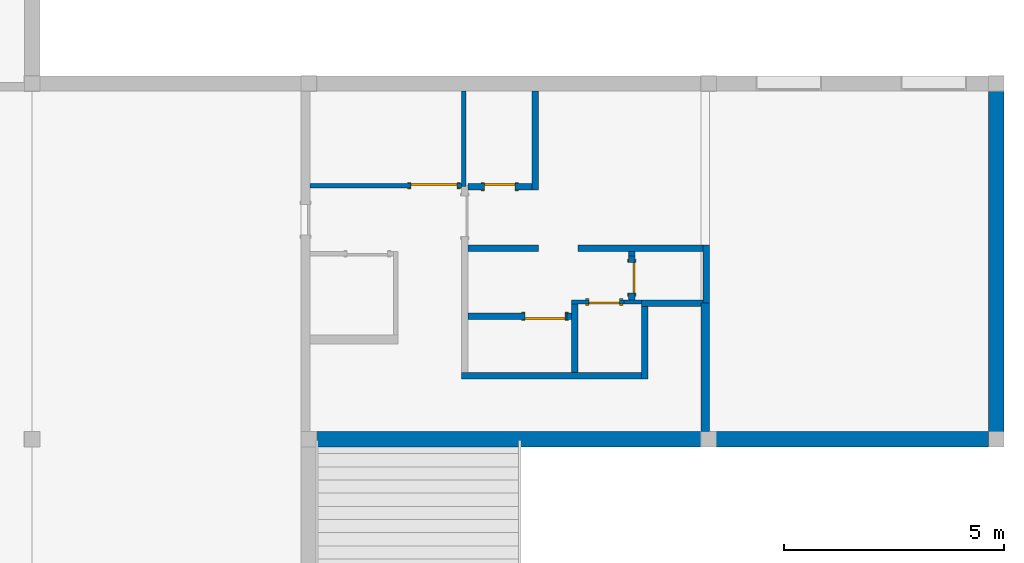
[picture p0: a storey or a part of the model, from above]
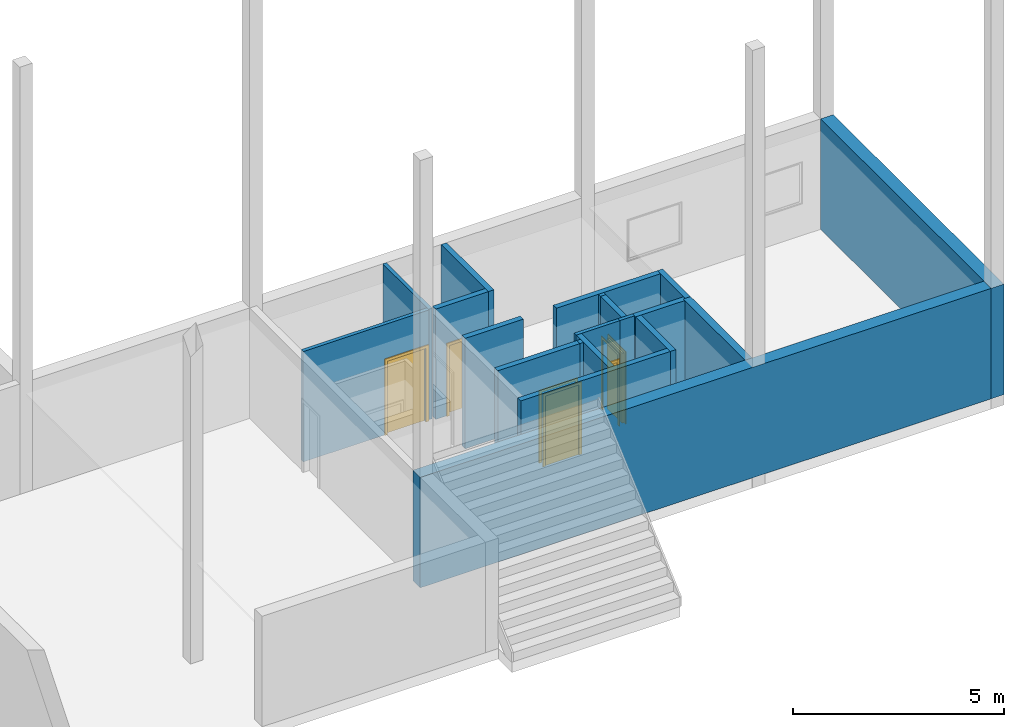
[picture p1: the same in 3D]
Properties of the parts of a building model (IFC2X3)

# File
Description: ViewDefinition [CoordinationView_V2.0]
File name: Project Number
Time: 2023-11-21T13:42:55+03:30
Written by: ODA SDAI 22.12
Made in: 23.0.10.18 - Exporter 23.0.10.18 - Alternate UI 23.0.10.18

# IfcProject, Project Number
LongName: Project Name; Phase: Project Status

# IfcSite, Default
RefLatitude: 42, 12, 46, 799999; RefLongitude: -71, -1, -58, -799999; RefElevation: 0 m
Pset_ProductRequirements - Category: Project Information

# IfcSite: Toyota_Prius_2007_8010:Toyota_Prius_2007_8010 (2)
Material: <Unnamed>
Pset_ProductRequirements - Category: Site
Name (Toyota_Prius_2007_8010:Toyota_Prius_2007_8010:...)
230649
230872

# IfcSite: Volvo-850_4217:Volvo-850_4217 (2)
Material: <Unnamed>
Pset_ProductRequirements - Category: Site
Name (Volvo-850_4217:Volvo-850_4217:...)
229891
230032

# IfcBuilding
Pset_BuildingCommon - NumberOfStoreys: 3
Pset_ProductRequirements - Category: Project Information

# IfcBuildingStorey: Level:8mm Head (3)
Pset_ProductRequirements - Category: Levels
Name | LongName = Pset_AirSideSystemInformation, Name = Pset_ProductRequirements, Name | Elevation (m)
B1 | B1 | -2.3
G0 | G0 | 1.2
F1 | F1 | 5.64

# IfcColumn: COLUMN:COLUMN, COLUMN:COLUMN:227022
In: B1
Type - PredefinedType: COLUMN
Type - Pset_ColumnCommon - IsExternal: no
Type - Pset_ProductRequirements - Category: Columns
Pset_ColumnCommon - Reference: COLUMN
Pset_QuantityTakeOff - Reference: COLUMN; sets with these values: 2

# IfcCovering: Compound Ceiling:Plain (9)
Type - PredefinedType: CEILING
Type - Pset_CoveringCommon - TotalThickness: 0.057 m
Type - Pset_ElementShading - Roughness: 0.3048 m
Type - Pset_ProductRequirements - Category: Ceilings
Material: Metal - Stud Layer 0.045 m, Plasterboard 0.012 m
Pset_CoveringCommon - Reference: Plain; sets with these values: 2
Name (Compound Ceiling:Plain:...) | In
231957 | B1
232175 | B1
232232 | B1
232270 | G0
232307 | G0
232344 | G0
232768 | F1
232807 | F1
232842 | F1

# IfcCovering: Roof Soffit:Generic - 300mm, Roof Soffit:Generic - 300mm:256773
In: F1
Type - PredefinedType: CEILING
Type - Pset_CoveringCommon - TotalThickness: 0.3 m
Type - Pset_ProductRequirements - Category: Roofs: Roof Soffits
Material: Default Roof 0.3 m
Pset_CoveringCommon - Reference: Generic - 300mm; sets with these values: 2

# IfcDoor: Double_8_lite_patio_door_5282:36x2" x 80" w/transom" (4)
Type - ParameterTakesPrecedence: no; Sizeable: no; Classification: C1020 (Uniformat); Material: <Unnamed>, Door - Panel (8), Glazing - Window Glazing (3), Finishes - Exterior - Trim (4), Finishes - Interior - Trim
Type - Pset_DoorCommon - IsExternal: no
Type - Pset_ProductRequirements - Category: Doors
OverallHeight: 2.4384 m; OverallWidth: 1.8288 m
Pset_DoorCommon - Reference: 36x2" x 80" w/transom"
Pset_QuantityTakeOff - Reference: 36x2" x 80" w/transom"
Name (Double_8_lite_patio_door_5282:36x2" x 80" w/transom":...) | In
226973 | B1
227042 | G0 | Material: <Unnamed>, Door - Panel, Glazing - Window Glazing, Finishes - Exterior - Trim, Finishes - Interior - Trim
227043 | G0
227113 | F1 | Material: <Unnamed>, Door - Panel, Glazing - Window Glazing, Finishes - Exterior - Trim, Finishes - Interior - Trim

# IfcDoor: M_Single-Flush:0762 x 2032mm (17)
Type - ParameterTakesPrecedence: no; Sizeable: no; Material: Door - Frame (2), Door - Panel
Type - Pset_DoorCommon - IsExternal: no
Type - Pset_ProductRequirements - Category: Doors
OverallHeight: 2.032 m; OverallWidth: 0.7 m
Pset_DoorCommon - Reference: 0762 x 2032mm
Pset_QuantityTakeOff - Reference: 0762 x 2032mm
Name (M_Single-Flush:0762 x 2032mm:...) | In | Material
227198 | F1
227199 | F1
227200 | F1 | Door - Frame, Door - Panel
227201 | F1 | Door - Frame, Door - Panel
227202 | F1 | Door - Frame, Door - Panel
227203 | F1 | Door - Frame, Door - Panel
227204 | F1 | Door - Frame, Door - Panel
227205 | F1 | Door - Frame, Door - Panel
227206 | F1 | Door - Frame, Door - Panel
227211 | G0 | Door - Frame, Door - Panel
227212 | G0 | Door - Frame, Door - Panel
227213 | G0 | Door - Frame, Door - Panel
227214 | G0 | Door - Frame, Door - Panel
227215 | B1
227216 | B1 | Door - Frame, Door - Panel
227217 | B1 | Door - Frame, Door - Panel
227218 | B1 | Door - Frame, Door - Panel

# IfcDoor: M_Single-Flush:0915 x 2032mm (3)
In: B1
Type - ParameterTakesPrecedence: no; Sizeable: no; Material: Door - Frame (2), Door - Panel
Type - Pset_DoorCommon - IsExternal: no
Type - Pset_ProductRequirements - Category: Doors
OverallHeight: 2.032 m; OverallWidth: 0.915 m
Pset_DoorCommon - Reference: 0915 x 2032mm
Pset_QuantityTakeOff - Reference: 0915 x 2032mm
Name (M_Single-Flush:0915 x 2032mm:...)
226975
226976
226977

# IfcDoor: M_Single-Flush:0915 x 2134mm (6)
Type - ParameterTakesPrecedence: no; Sizeable: no; Material: Door - Frame (2), Door - Panel
Type - Pset_DoorCommon - IsExternal: no
Type - Pset_ProductRequirements - Category: Doors
OverallHeight: 2.134 m; OverallWidth: 1.05 m
Pset_DoorCommon - Reference: 0915 x 2134mm
Pset_QuantityTakeOff - Reference: 0915 x 2134mm
Name (M_Single-Flush:0915 x 2134mm:...) | In | Material
226974 | B1
226996 | G0
226997 | G0 | Door - Frame, Door - Panel
226999 | G0 | Door - Frame, Door - Panel
227009 | G0 | Door - Frame, Door - Panel
227010 | G0 | Door - Frame, Door - Panel

# IfcDoor: Parametric_Operable_Sliding_Door_6386.0004:3000W x 2400H (2)
In: F1
Type - ParameterTakesPrecedence: no; Sizeable: no; Material: Window Glass (2), Window Frame (2)
Type - Pset_DoorCommon - IsExternal: no
Type - Pset_ProductRequirements - Category: Doors
Type - IfcPermeableCoveringProperties - FrameThickness: 0.05 m
OverallHeight: 2.2 m; OverallWidth: 1 m
Pset_DoorCommon - Reference: 3000W x 2400H
Pset_QuantityTakeOff - Reference: 3000W x 2400H
Name (Parametric_Operable_Sliding_Door_6386.0004:3000W x 2400H:...)
227209
227210 | Material: Window Glass, Window Frame

# IfcDoor: Parametric_Operable_Sliding_Door_6386.0004:5M (3)
Type - ParameterTakesPrecedence: no; Sizeable: no; Material: Window Glass (2), Window Frame (2)
Type - Pset_DoorCommon - IsExternal: no
Type - Pset_ProductRequirements - Category: Doors
Type - IfcPermeableCoveringProperties - FrameThickness: 0.05 m
OverallHeight: 2.2 m; OverallWidth: 5 m
Pset_DoorCommon - Reference: 5M
Pset_QuantityTakeOff - Reference: 5M
Name (Parametric_Operable_Sliding_Door_6386.0004:5M:...) | In | Material
227177 | F1
227988 | F1 | Window Glass, Window Frame
228184 | G0 | Window Glass, Window Frame

# IfcMember: Stringer:Stringer - 50 mm Width (2)
In: B1
Type - PredefinedType: STRINGER
Material: <Unnamed>
Pset_MemberCommon - IsExternal: no; Reference: Stringer - 50 mm Width; Slope: 90 deg
Pset_ProductRequirements - Category: Stairs: Supports
Pset_QuantityTakeOff - Reference: Stringer - 50 mm Width
Name (Assembled Stair:Stair:...)
228969 Stringer 1
228969 Stringer 2

# IfcOpeningElement: Opening (44)
Name | In
Basic Wall:CW 100:227006 | G0 | Pset_OpeningElementCommon - Reference: 0915 x 2134mm; sets with these values: 2; Pset_ProductRequirements - Category: Doors
M_Fixed:0915 x 1220mm:227227:1 | B1
M_Fixed:0915 x 1220mm:227228:1 | B1
Double_8_lite_patio_door_5282:36x2" x 80" w/transom":226973:1 | B1
M_Single-Flush:0762 x 2032mm:227218:1 | B1
M_Single-Flush:0915 x 2032mm:226976:1 | B1
M_Single-Flush:0915 x 2134mm:226974:1 | B1
M_Single-Flush:0762 x 2032mm:227217:1 | B1
M_Single-Flush:0915 x 2032mm:226975:1 | B1
M_Single-Flush:0915 x 2032mm:226977:1 | B1
M_Single-Flush:0762 x 2032mm:227216:1 | B1
M_Single-Flush:0762 x 2032mm:227215:1 | B1
M_Fixed:0915 x 1830mm:227056:1 | G0
M_Fixed:0915 x 1220mm:227219:1 | G0
M_Fixed:0915 x 1220mm:227220:1 | G0
Double_8_lite_patio_door_5282:36x2" x 80" w/transom":227043:1 | G0
Parametric_Operable_Sliding_Door_6386.0004:5M:228184:1 | G0
M_Single-Flush:0762 x 2032mm:227214:1 | G0
Double_8_lite_patio_door_5282:36x2" x 80" w/transom":227042:1 | G0
M_Single-Flush:0762 x 2032mm:227211:1 | G0
M_Single-Flush:0915 x 2134mm:226996:1 | G0
M_Single-Flush:0762 x 2032mm:227212:1 | G0
M_Single-Flush:0762 x 2032mm:227213:1 | G0
M_Single-Flush:0915 x 2134mm:226997:1 | G0
M_Single-Flush:0915 x 2134mm:226999:1 | G0
M_Single-Flush:0915 x 2134mm:227010:1 | G0
M_Single-Flush:0915 x 2134mm:227009:1 | G0
M_Single-Flush:0762 x 2032mm:227198:1 | F1
Parametric_Operable_Sliding_Door_6386.0004:5M:227988:1 | F1
M_Fixed:0915 x 1220mm:227196:1 | F1
M_Fixed:0915 x 1220mm:227197:1 | F1
Parametric_Operable_Sliding_Door_6386.0004:3000W x 2400H:227210:1 | F1
Parametric_Operable_Sliding_Door_6386.0004:3000W x 2400H:227209:1 | F1
M_Single-Flush:0762 x 2032mm:227204:1 | F1
M_Single-Flush:0762 x 2032mm:227205:1 | F1
Double_8_lite_patio_door_5282:36x2" x 80" w/transom":227113:1 | F1
M_Fixed:0915 x 1220mm:227114:1 | F1
Parametric_Operable_Sliding_Door_6386.0004:5M:227177:1 | F1
M_Single-Flush:0762 x 2032mm:227206:1 | F1
M_Single-Flush:0762 x 2032mm:227201:1 | F1
M_Single-Flush:0762 x 2032mm:227199:1 | F1
M_Single-Flush:0762 x 2032mm:227200:1 | F1
M_Single-Flush:0762 x 2032mm:227203:1 | F1
M_Single-Flush:0762 x 2032mm:227202:1 | F1

# IfcRailing: Railing:1100mm (5)
Pset_ProductRequirements - Category: Railings
Pset_QuantityTakeOff - Reference: 1100mm
Pset_RailingCommon - IsExternal: no; Reference: 1100mm; Height: 1.2192 m
Name (Railing:1100mm:...) | In | Material
227187 | F1 | <Unnamed> (26)
227192 | F1 | <Unnamed> (48)
227223 | G0 | <Unnamed> (48)
228103 | F1 | <Unnamed> (25)
228249 | G0 | <Unnamed> (25)

# IfcSlab: Floor:Generic 300mm (4)
Type - PredefinedType: FLOOR; Material: Default Floor 0.3 m
Type - Pset_ElementShading - Roughness: 0.3048 m
Type - Pset_ProductRequirements - Category: Floors
Type - Pset_SlabCommon - IsExternal: no
Pset_QuantityTakeOff - Reference: Generic 300mm; sets with these values: 2
Pset_SlabCommon - LoadBearing: no; Reference: Generic 300mm; PitchAngle: 0 deg
Name (Floor:Generic 300mm:...) | In
227025 | B1
227046 | G0
227059 | F1
227180 | F1

# IfcStair: Assembled Stair:190mm max riser 250mm going, Assembled Stair:Stair:228969
In: B1
ShapeType: STRAIGHT_RUN_STAIR
Pset_ProductRequirements - Category: Stairs
Pset_QuantityTakeOff - Reference: 190mm max riser 250mm going
Pset_StairCommon - IsExternal: no; Reference: 190mm max riser 250mm going; NumberOfRiser: 14; NumberOfTreads: 13; RiserHeight: 0.264 m; TreadLength: 0.3 m

# IfcStairFlight: Non-Monolithic Run:50 mm Tread 13 mm Riser, Assembled Stair:Stair:228969 Run 1
In: B1
Type - PredefinedType: STRAIGHT
Type - Pset_ProductRequirements - Category: Stairs: Runs
Type - Pset_StairFlightCommon - NosingLength: 0 m
NumberOfRiser: 14; NumberOfTreads: 13; RiserHeight: 0.866142 m; TreadLength: 0.984252 m; Material: <Unnamed>
Pset_QuantityTakeOff - Reference: 50 mm Tread 13 mm Riser
Pset_StairFlightCommon - Reference: 50 mm Tread 13 mm Riser; NumberOfRiser: 14; NumberOfTreads: 13; RiserHeight: 0.264 m; TreadLength: 0.3 m; WalkingLineOffset: 7.48336 m; TreadLengthAtOffset: 0.3 m; TreadLengthAtInnerSide: 0.3 m

# IfcWallStandardCase: Basic Wall:CW 100 (53)
Type - PredefinedType: STANDARD; Material: Masonry - Concrete Block 0.1 m
Type - Pset_ElementShading - Roughness: 0.3048 m
Type - Pset_ProductRequirements - Category: Walls
Type - Pset_WallCommon - IsExternal: yes
Pset_QuantityTakeOff - Reference: CW 100; sets with these values: 2
Pset_WallCommon - ExtendToStructure: no; LoadBearing: no; Reference: CW 100
Name (Basic Wall:CW 100:...) | In
226934 | B1
226935 | B1
226936 | B1
226937 | B1
226952 | B1
226953 | B1
226979 | G0
226980 | G0
226981 | G0
226982 | G0
226983 | G0
226984 | G0
226985 | G0
226986 | G0
226989 | G0
226990 | G0
226991 | G0
226992 | G0
226993 | G0
226994 | G0
226995 | G0
226998 | G0
227000 | G0
227003 | G0
227004 | G0
227005 | G0
227006 | G0
227007 | G0
227008 | G0
227055 | G0
227078 | F1
227079 | F1
227080 | F1
227081 | F1
227082 | F1
227091 | F1
227092 | F1
227093 | F1
227094 | F1
227095 | F1
227096 | F1
227097 | F1
227098 | F1
227099 | F1
227100 | F1
227101 | F1
227102 | F1
227103 | F1
227104 | F1
227105 | F1
227106 | F1
227111 | F1
227112 | F1

# IfcWallStandardCase: Basic Wall:CW 102-50-100p (4)
In: B1
Type - PredefinedType: STANDARD; Material: Masonry - Concrete Block 0.35 m
Type - Pset_ElementShading - Roughness: 0.3048 m
Type - Pset_ProductRequirements - Category: Walls
Type - Pset_WallCommon - IsExternal: yes
Pset_QuantityTakeOff - Reference: CW 102-50-100p; sets with these values: 2
Pset_WallCommon - ExtendToStructure: no; LoadBearing: no; Reference: CW 102-50-100p
Name (Basic Wall:CW 102-50-100p:...)
226925
226926
226927
227776

# IfcWallStandardCase: Basic Wall:CW 150 (22)
Type - PredefinedType: STANDARD; Material: Masonry - Concrete Block 0.15 m
Type - Pset_ElementShading - Roughness: 0.3048 m
Type - Pset_ProductRequirements - Category: Walls
Type - Pset_WallCommon - IsExternal: yes
Pset_QuantityTakeOff - Reference: CW 150; sets with these values: 2
Pset_WallCommon - ExtendToStructure: no; LoadBearing: no; Reference: CW 150
Name (Basic Wall:CW 150:...) | In
226938 | B1
226939 | B1
226941 | B1
226942 | B1
226943 | B1
226944 | B1
226945 | B1
226946 | B1
226947 | B1
226948 | B1
226949 | B1
226950 | B1
226951 | B1
226954 | B1
226978 | G0
227036 | G0
227038 | G0
227039 | G0
227083 | F1
227090 | F1
227175 | F1
227176 | F1

# IfcWallStandardCase: Basic Wall:CW 200 (35)
Type - PredefinedType: STANDARD; Material: Masonry - Concrete Block 0.2 m
Type - Pset_ElementShading - Roughness: 0.3048 m
Type - Pset_ProductRequirements - Category: Walls
Type - Pset_WallCommon - IsExternal: yes
Pset_QuantityTakeOff - Reference: CW 200; sets with these values: 2
Pset_WallCommon - LoadBearing: no; Reference: CW 200
Name (Basic Wall:CW 200:...) | In | ExtendToStructure
226931 | B1 | no
226932 | B1 | no
226933 | B1 | no
226940 | B1 | no
226955 | G0 | yes
226956 | G0 | yes
226957 | G0 | no
226958 | G0 | no
226959 | G0 | no
226960 | G0 | no
226961 | G0 | no
226962 | G0 | no
226963 | G0 | no
226964 | G0 | no
226965 | G0 | no
226966 | G0 | no
226967 | G0 | no
226968 | G0 | no
226972 | B1 | no
227035 | G0 | no
227037 | G0 | no
227068 | F1 | no
227069 | F1 | no
227070 | F1 | no
227071 | F1 | no
227072 | F1 | no
227073 | F1 | no
227074 | F1 | no
227075 | F1 | no
227084 | F1 | no
227085 | F1 | no
227086 | F1 | no
227087 | F1 | no
227088 | F1 | no
227089 | F1 | no

# IfcWallStandardCase: Basic Wall:CW 260 (4)
Type - PredefinedType: STANDARD; Material: Masonry - Concrete Block 0.26 m
Type - Pset_ElementShading - Roughness: 0.3048 m
Type - Pset_ProductRequirements - Category: Walls
Type - Pset_WallCommon - IsExternal: yes
Pset_QuantityTakeOff - Reference: CW 260; sets with these values: 2
Pset_WallCommon - ExtendToStructure: no; LoadBearing: no; Reference: CW 260
Name (Basic Wall:CW 260:...) | In
226969 | G0
226970 | G0
227076 | F1
227077 | F1

# IfcWallStandardCase: Basic Wall:CW 350 (4)
In: B1
Type - PredefinedType: STANDARD; Material: Masonry - Concrete Block 0.35 m
Type - Pset_ElementShading - Roughness: 0.3048 m
Type - Pset_ProductRequirements - Category: Walls
Type - Pset_WallCommon - IsExternal: yes
Pset_QuantityTakeOff - Reference: CW 350; sets with these values: 2
Pset_WallCommon - Reference: CW 350; ExtendToStructure: no; LoadBearing: no
Name (Basic Wall:CW 350:...)
226924
226929
226930
226971

# IfcWallStandardCase: Basic Wall:CW 50 (12)
Type - PredefinedType: STANDARD; Material: Masonry - Concrete Block 0.05 m
Type - Pset_ElementShading - Roughness: 0.3048 m
Type - Pset_ProductRequirements - Category: Walls
Type - Pset_WallCommon - IsExternal: yes
Pset_QuantityTakeOff - Reference: CW 50; sets with these values: 2
Pset_WallCommon - ExtendToStructure: no; LoadBearing: no; Reference: CW 50
Name (Basic Wall:CW 50:...) | In
226987 | G0
226988 | G0
227001 | G0
227002 | G0
227040 | G0
227041 | G0
227107 | F1
227108 | F1
227109 | F1
227110 | F1
227207 | F1
227208 | F1

# IfcWindow: M_Fixed:0915 x 1220mm (7)
Type - ParameterTakesPrecedence: no; Sizeable: no; Material: Glass, Sash (3)
Type - Pset_ProductRequirements - Category: Windows
Type - Pset_WindowCommon - IsExternal: no
OverallHeight: 1.22 m; OverallWidth: 1.5 m
Pset_QuantityTakeOff - Reference: 0915 x 1220mm
Pset_WindowCommon - Reference: 0915 x 1220mm
Name (M_Fixed:0915 x 1220mm:...) | In | Material
227114 | F1 | Pset_WindowCommon - IsExternal: yes
227196 | F1 | Glass, Sash
227197 | F1 | Glass, Sash
227219 | G0 | Glass, Sash
227220 | G0 | Glass, Sash
227227 | B1
227228 | B1 | Glass, Sash

# IfcWindow: M_Fixed:0915 x 1830mm, M_Fixed:0915 x 1830mm:227056
In: G0
Type - ParameterTakesPrecedence: no; Sizeable: no; Material: Glass, Sash (3)
Type - Pset_ProductRequirements - Category: Windows
Type - Pset_WindowCommon - IsExternal: no
OverallHeight: 1.83 m; OverallWidth: 5 m
Pset_QuantityTakeOff - Reference: 0915 x 1830mm
Pset_WindowCommon - IsExternal: yes; Reference: 0915 x 1830mm
